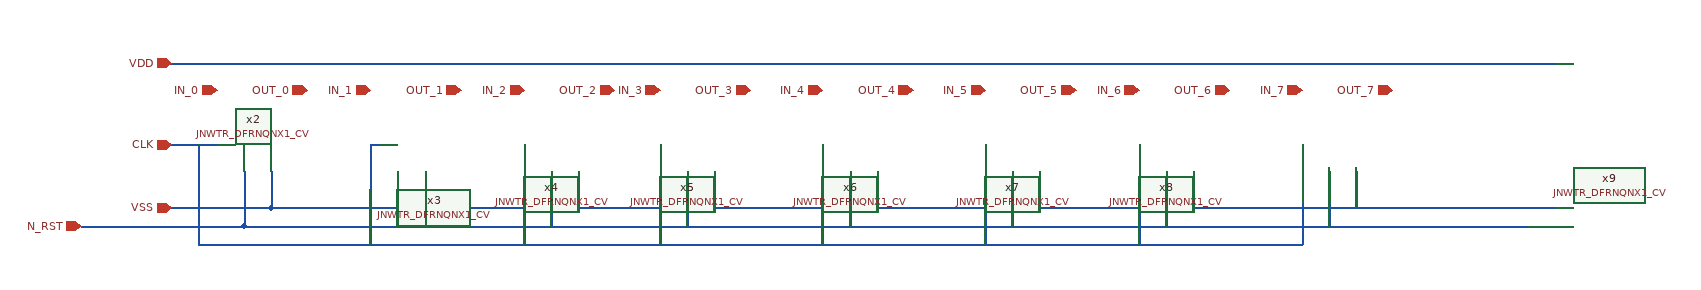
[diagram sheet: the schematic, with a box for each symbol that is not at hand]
v {xschem version=3.4.6 file_version=1.2}
G {}
K {}
V {}
S {}
E {}
N -90 -10 1330 -10 {lab=VDD}
N -90 110 -90 150 {lab=VSS}
N -90 150 80 150 {lab=VSS}
N 80 110 80 150 {lab=VSS}
N 80 150 1330 150 {lab=VSS}
N 1110 110 1110 150 {lab=VSS}
N 930 110 930 150 {lab=VSS}
N 760 110 760 150 {lab=VSS}
N 580 110 580 150 {lab=VSS}
N 400 110 400 150 {lab=VSS}
N 250 110 250 150 {lab=VSS}
N -120 110 -120 170 {lab=#net1}
N -120 170 1300 170 {lab=#net1}
N 1080 110 1080 170 {lab=#net1}
N 900 110 900 170 {lab=#net1}
N 730 110 730 170 {lab=#net1}
N 550 110 550 170 {lab=#net1}
N 370 110 370 170 {lab=#net1}
N 220 110 220 170 {lab=#net1}
N 50 110 50 170 {lab=#net1}
N -190 80 -150 80 {lab=CLK}
N -200 170 -140 170 {lab=#net1}
N -140 170 -120 170 {lab=#net1}
N -200 80 -190 80 {lab=CLK}
N -200 -10 -90 -10 {lab=VDD}
N 20 80 30 80 {lab=CLK}
N -170 80 -170 190 {lab=CLK}
N -170 190 1050 190 {lab=CLK}
N 1050 80 1050 190 {lab=CLK}
N 870 80 870 190 {lab=CLK}
N 700 80 700 190 {lab=CLK}
N 520 80 520 190 {lab=CLK}
N 340 80 340 190 {lab=CLK}
N 190 80 190 190 {lab=CLK}
N 20 80 20 190 {lab=CLK}
N -200 150 -90 150 {lab=VSS}
N -300 170 -200 170 {lab=#net1}
C {JNW_TR_SKY130A/JNWTR_DFRNQNX1_CV.sym} -150 80 0 0 {name=x2 }
C {JNW_TR_SKY130A/JNWTR_DFRNQNX1_CV.sym} 20 80 0 0 {name=x3 }
C {JNW_TR_SKY130A/JNWTR_DFRNQNX1_CV.sym} 190 80 0 0 {name=x4 }
C {JNW_TR_SKY130A/JNWTR_DFRNQNX1_CV.sym} 340 80 0 0 {name=x5 }
C {JNW_TR_SKY130A/JNWTR_DFRNQNX1_CV.sym} 520 80 0 0 {name=x6 }
C {JNW_TR_SKY130A/JNWTR_DFRNQNX1_CV.sym} 700 80 0 0 {name=x7 }
C {JNW_TR_SKY130A/JNWTR_DFRNQNX1_CV.sym} 870 80 0 0 {name=x8 }
C {JNW_TR_SKY130A/JNWTR_DFRNQNX1_CV.sym} 1050 80 0 0 {name=x9 }
C {devices/ipin.sym} -200 80 0 0 {name=p2 lab=CLK
}
C {devices/ipin.sym} -200 -10 0 0 {name=p3 lab=VDD}
C {devices/ipin.sym} -300 170 0 0 {name=p5 lab=N_RST}
C {devices/ipin.sym} -150 20 1 0 {name=p4 lab=IN_0}
C {devices/ipin.sym} 20 20 1 0 {name=p14 lab=IN_1}
C {devices/ipin.sym} 190 20 1 0 {name=p15 lab=IN_2}
C {devices/ipin.sym} 340 20 1 0 {name=p16 lab=IN_3}
C {devices/ipin.sym} 520 20 1 0 {name=p17 lab=IN_4
}
C {devices/ipin.sym} 700 20 1 0 {name=p18 lab=IN_5
}
C {devices/ipin.sym} 870 20 1 0 {name=p19 lab=IN_6}
C {devices/ipin.sym} 1050 20 1 0 {name=p20 lab=IN_7}
C {devices/ipin.sym} -50 20 1 0 {name=p1 lab=OUT_0}
C {devices/ipin.sym} 120 20 1 0 {name=p13 lab=OUT_1}
C {devices/ipin.sym} 290 20 1 0 {name=p21 lab=OUT_2}
C {devices/ipin.sym} 440 20 1 0 {name=p22 lab=OUT_3}
C {devices/ipin.sym} 620 20 1 0 {name=p23 lab=OUT_4
}
C {devices/ipin.sym} 800 20 1 0 {name=p24 lab=OUT_5}
C {devices/ipin.sym} 970 20 1 0 {name=p25 lab=OUT_6}
C {devices/ipin.sym} 1150 20 1 0 {name=p26 lab=OUT_7}
C {devices/ipin.sym} -200 150 0 0 {name=p6 lab=VSS}
